# Generated by FakeRAM 2.0
VERSION 5.7 ;
BUSBITCHARS "[]" ;
PROPERTYDEFINITIONS
  MACRO width INTEGER ;
  MACRO depth INTEGER ;
  MACRO banks INTEGER ;
END PROPERTYDEFINITIONS
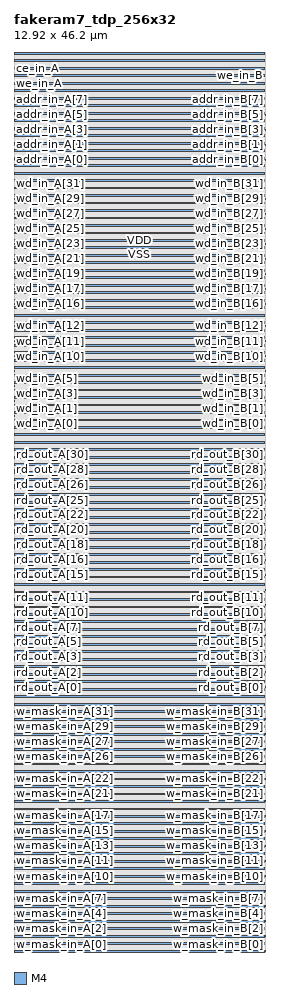
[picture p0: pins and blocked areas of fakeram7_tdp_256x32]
MACRO fakeram7_tdp_256x32
  PROPERTY width 32 ;
  PROPERTY depth 256 ;
  PROPERTY banks 2 ;
  FOREIGN fakeram7_tdp_256x32 0 0 ;
  SYMMETRY X Y ;
  SIZE 12.920 BY 46.200 ;
  CLASS BLOCK ;
  PIN w_mask_in_A[0]
    DIRECTION INPUT ;
    USE SIGNAL ;
    SHAPE ABUTMENT ;
    PORT
      LAYER M4 ;
      RECT 0.000 0.048 0.024 0.072 ;
    END
  END w_mask_in_A[0]
  PIN w_mask_in_B[0]
    DIRECTION INPUT ;
    USE SIGNAL ;
    SHAPE ABUTMENT ;
    PORT
      LAYER M4 ;
      RECT 12.896 0.048 12.920 0.072 ;
    END
  END w_mask_in_B[0]
  PIN w_mask_in_A[1]
    DIRECTION INPUT ;
    USE SIGNAL ;
    SHAPE ABUTMENT ;
    PORT
      LAYER M4 ;
      RECT 0.000 0.432 0.024 0.456 ;
    END
  END w_mask_in_A[1]
  PIN w_mask_in_B[1]
    DIRECTION INPUT ;
    USE SIGNAL ;
    SHAPE ABUTMENT ;
    PORT
      LAYER M4 ;
      RECT 12.896 0.432 12.920 0.456 ;
    END
  END w_mask_in_B[1]
  PIN w_mask_in_A[2]
    DIRECTION INPUT ;
    USE SIGNAL ;
    SHAPE ABUTMENT ;
    PORT
      LAYER M4 ;
      RECT 0.000 0.816 0.024 0.840 ;
    END
  END w_mask_in_A[2]
  PIN w_mask_in_B[2]
    DIRECTION INPUT ;
    USE SIGNAL ;
    SHAPE ABUTMENT ;
    PORT
      LAYER M4 ;
      RECT 12.896 0.816 12.920 0.840 ;
    END
  END w_mask_in_B[2]
  PIN w_mask_in_A[3]
    DIRECTION INPUT ;
    USE SIGNAL ;
    SHAPE ABUTMENT ;
    PORT
      LAYER M4 ;
      RECT 0.000 1.200 0.024 1.224 ;
    END
  END w_mask_in_A[3]
  PIN w_mask_in_B[3]
    DIRECTION INPUT ;
    USE SIGNAL ;
    SHAPE ABUTMENT ;
    PORT
      LAYER M4 ;
      RECT 12.896 1.200 12.920 1.224 ;
    END
  END w_mask_in_B[3]
  PIN w_mask_in_A[4]
    DIRECTION INPUT ;
    USE SIGNAL ;
    SHAPE ABUTMENT ;
    PORT
      LAYER M4 ;
      RECT 0.000 1.584 0.024 1.608 ;
    END
  END w_mask_in_A[4]
  PIN w_mask_in_B[4]
    DIRECTION INPUT ;
    USE SIGNAL ;
    SHAPE ABUTMENT ;
    PORT
      LAYER M4 ;
      RECT 12.896 1.584 12.920 1.608 ;
    END
  END w_mask_in_B[4]
  PIN w_mask_in_A[5]
    DIRECTION INPUT ;
    USE SIGNAL ;
    SHAPE ABUTMENT ;
    PORT
      LAYER M4 ;
      RECT 0.000 1.968 0.024 1.992 ;
    END
  END w_mask_in_A[5]
  PIN w_mask_in_B[5]
    DIRECTION INPUT ;
    USE SIGNAL ;
    SHAPE ABUTMENT ;
    PORT
      LAYER M4 ;
      RECT 12.896 1.968 12.920 1.992 ;
    END
  END w_mask_in_B[5]
  PIN w_mask_in_A[6]
    DIRECTION INPUT ;
    USE SIGNAL ;
    SHAPE ABUTMENT ;
    PORT
      LAYER M4 ;
      RECT 0.000 2.352 0.024 2.376 ;
    END
  END w_mask_in_A[6]
  PIN w_mask_in_B[6]
    DIRECTION INPUT ;
    USE SIGNAL ;
    SHAPE ABUTMENT ;
    PORT
      LAYER M4 ;
      RECT 12.896 2.352 12.920 2.376 ;
    END
  END w_mask_in_B[6]
  PIN w_mask_in_A[7]
    DIRECTION INPUT ;
    USE SIGNAL ;
    SHAPE ABUTMENT ;
    PORT
      LAYER M4 ;
      RECT 0.000 2.736 0.024 2.760 ;
    END
  END w_mask_in_A[7]
  PIN w_mask_in_B[7]
    DIRECTION INPUT ;
    USE SIGNAL ;
    SHAPE ABUTMENT ;
    PORT
      LAYER M4 ;
      RECT 12.896 2.736 12.920 2.760 ;
    END
  END w_mask_in_B[7]
  PIN w_mask_in_A[8]
    DIRECTION INPUT ;
    USE SIGNAL ;
    SHAPE ABUTMENT ;
    PORT
      LAYER M4 ;
      RECT 0.000 3.120 0.024 3.144 ;
    END
  END w_mask_in_A[8]
  PIN w_mask_in_B[8]
    DIRECTION INPUT ;
    USE SIGNAL ;
    SHAPE ABUTMENT ;
    PORT
      LAYER M4 ;
      RECT 12.896 3.120 12.920 3.144 ;
    END
  END w_mask_in_B[8]
  PIN w_mask_in_A[9]
    DIRECTION INPUT ;
    USE SIGNAL ;
    SHAPE ABUTMENT ;
    PORT
      LAYER M4 ;
      RECT 0.000 3.504 0.024 3.528 ;
    END
  END w_mask_in_A[9]
  PIN w_mask_in_B[9]
    DIRECTION INPUT ;
    USE SIGNAL ;
    SHAPE ABUTMENT ;
    PORT
      LAYER M4 ;
      RECT 12.896 3.504 12.920 3.528 ;
    END
  END w_mask_in_B[9]
  PIN w_mask_in_A[10]
    DIRECTION INPUT ;
    USE SIGNAL ;
    SHAPE ABUTMENT ;
    PORT
      LAYER M4 ;
      RECT 0.000 3.888 0.024 3.912 ;
    END
  END w_mask_in_A[10]
  PIN w_mask_in_B[10]
    DIRECTION INPUT ;
    USE SIGNAL ;
    SHAPE ABUTMENT ;
    PORT
      LAYER M4 ;
      RECT 12.896 3.888 12.920 3.912 ;
    END
  END w_mask_in_B[10]
  PIN w_mask_in_A[11]
    DIRECTION INPUT ;
    USE SIGNAL ;
    SHAPE ABUTMENT ;
    PORT
      LAYER M4 ;
      RECT 0.000 4.272 0.024 4.296 ;
    END
  END w_mask_in_A[11]
  PIN w_mask_in_B[11]
    DIRECTION INPUT ;
    USE SIGNAL ;
    SHAPE ABUTMENT ;
    PORT
      LAYER M4 ;
      RECT 12.896 4.272 12.920 4.296 ;
    END
  END w_mask_in_B[11]
  PIN w_mask_in_A[12]
    DIRECTION INPUT ;
    USE SIGNAL ;
    SHAPE ABUTMENT ;
    PORT
      LAYER M4 ;
      RECT 0.000 4.656 0.024 4.680 ;
    END
  END w_mask_in_A[12]
  PIN w_mask_in_B[12]
    DIRECTION INPUT ;
    USE SIGNAL ;
    SHAPE ABUTMENT ;
    PORT
      LAYER M4 ;
      RECT 12.896 4.656 12.920 4.680 ;
    END
  END w_mask_in_B[12]
  PIN w_mask_in_A[13]
    DIRECTION INPUT ;
    USE SIGNAL ;
    SHAPE ABUTMENT ;
    PORT
      LAYER M4 ;
      RECT 0.000 5.040 0.024 5.064 ;
    END
  END w_mask_in_A[13]
  PIN w_mask_in_B[13]
    DIRECTION INPUT ;
    USE SIGNAL ;
    SHAPE ABUTMENT ;
    PORT
      LAYER M4 ;
      RECT 12.896 5.040 12.920 5.064 ;
    END
  END w_mask_in_B[13]
  PIN w_mask_in_A[14]
    DIRECTION INPUT ;
    USE SIGNAL ;
    SHAPE ABUTMENT ;
    PORT
      LAYER M4 ;
      RECT 0.000 5.424 0.024 5.448 ;
    END
  END w_mask_in_A[14]
  PIN w_mask_in_B[14]
    DIRECTION INPUT ;
    USE SIGNAL ;
    SHAPE ABUTMENT ;
    PORT
      LAYER M4 ;
      RECT 12.896 5.424 12.920 5.448 ;
    END
  END w_mask_in_B[14]
  PIN w_mask_in_A[15]
    DIRECTION INPUT ;
    USE SIGNAL ;
    SHAPE ABUTMENT ;
    PORT
      LAYER M4 ;
      RECT 0.000 5.808 0.024 5.832 ;
    END
  END w_mask_in_A[15]
  PIN w_mask_in_B[15]
    DIRECTION INPUT ;
    USE SIGNAL ;
    SHAPE ABUTMENT ;
    PORT
      LAYER M4 ;
      RECT 12.896 5.808 12.920 5.832 ;
    END
  END w_mask_in_B[15]
  PIN w_mask_in_A[16]
    DIRECTION INPUT ;
    USE SIGNAL ;
    SHAPE ABUTMENT ;
    PORT
      LAYER M4 ;
      RECT 0.000 6.192 0.024 6.216 ;
    END
  END w_mask_in_A[16]
  PIN w_mask_in_B[16]
    DIRECTION INPUT ;
    USE SIGNAL ;
    SHAPE ABUTMENT ;
    PORT
      LAYER M4 ;
      RECT 12.896 6.192 12.920 6.216 ;
    END
  END w_mask_in_B[16]
  PIN w_mask_in_A[17]
    DIRECTION INPUT ;
    USE SIGNAL ;
    SHAPE ABUTMENT ;
    PORT
      LAYER M4 ;
      RECT 0.000 6.576 0.024 6.600 ;
    END
  END w_mask_in_A[17]
  PIN w_mask_in_B[17]
    DIRECTION INPUT ;
    USE SIGNAL ;
    SHAPE ABUTMENT ;
    PORT
      LAYER M4 ;
      RECT 12.896 6.576 12.920 6.600 ;
    END
  END w_mask_in_B[17]
  PIN w_mask_in_A[18]
    DIRECTION INPUT ;
    USE SIGNAL ;
    SHAPE ABUTMENT ;
    PORT
      LAYER M4 ;
      RECT 0.000 6.960 0.024 6.984 ;
    END
  END w_mask_in_A[18]
  PIN w_mask_in_B[18]
    DIRECTION INPUT ;
    USE SIGNAL ;
    SHAPE ABUTMENT ;
    PORT
      LAYER M4 ;
      RECT 12.896 6.960 12.920 6.984 ;
    END
  END w_mask_in_B[18]
  PIN w_mask_in_A[19]
    DIRECTION INPUT ;
    USE SIGNAL ;
    SHAPE ABUTMENT ;
    PORT
      LAYER M4 ;
      RECT 0.000 7.344 0.024 7.368 ;
    END
  END w_mask_in_A[19]
  PIN w_mask_in_B[19]
    DIRECTION INPUT ;
    USE SIGNAL ;
    SHAPE ABUTMENT ;
    PORT
      LAYER M4 ;
      RECT 12.896 7.344 12.920 7.368 ;
    END
  END w_mask_in_B[19]
  PIN w_mask_in_A[20]
    DIRECTION INPUT ;
    USE SIGNAL ;
    SHAPE ABUTMENT ;
    PORT
      LAYER M4 ;
      RECT 0.000 7.728 0.024 7.752 ;
    END
  END w_mask_in_A[20]
  PIN w_mask_in_B[20]
    DIRECTION INPUT ;
    USE SIGNAL ;
    SHAPE ABUTMENT ;
    PORT
      LAYER M4 ;
      RECT 12.896 7.728 12.920 7.752 ;
    END
  END w_mask_in_B[20]
  PIN w_mask_in_A[21]
    DIRECTION INPUT ;
    USE SIGNAL ;
    SHAPE ABUTMENT ;
    PORT
      LAYER M4 ;
      RECT 0.000 8.112 0.024 8.136 ;
    END
  END w_mask_in_A[21]
  PIN w_mask_in_B[21]
    DIRECTION INPUT ;
    USE SIGNAL ;
    SHAPE ABUTMENT ;
    PORT
      LAYER M4 ;
      RECT 12.896 8.112 12.920 8.136 ;
    END
  END w_mask_in_B[21]
  PIN w_mask_in_A[22]
    DIRECTION INPUT ;
    USE SIGNAL ;
    SHAPE ABUTMENT ;
    PORT
      LAYER M4 ;
      RECT 0.000 8.496 0.024 8.520 ;
    END
  END w_mask_in_A[22]
  PIN w_mask_in_B[22]
    DIRECTION INPUT ;
    USE SIGNAL ;
    SHAPE ABUTMENT ;
    PORT
      LAYER M4 ;
      RECT 12.896 8.496 12.920 8.520 ;
    END
  END w_mask_in_B[22]
  PIN w_mask_in_A[23]
    DIRECTION INPUT ;
    USE SIGNAL ;
    SHAPE ABUTMENT ;
    PORT
      LAYER M4 ;
      RECT 0.000 8.880 0.024 8.904 ;
    END
  END w_mask_in_A[23]
  PIN w_mask_in_B[23]
    DIRECTION INPUT ;
    USE SIGNAL ;
    SHAPE ABUTMENT ;
    PORT
      LAYER M4 ;
      RECT 12.896 8.880 12.920 8.904 ;
    END
  END w_mask_in_B[23]
  PIN w_mask_in_A[24]
    DIRECTION INPUT ;
    USE SIGNAL ;
    SHAPE ABUTMENT ;
    PORT
      LAYER M4 ;
      RECT 0.000 9.264 0.024 9.288 ;
    END
  END w_mask_in_A[24]
  PIN w_mask_in_B[24]
    DIRECTION INPUT ;
    USE SIGNAL ;
    SHAPE ABUTMENT ;
    PORT
      LAYER M4 ;
      RECT 12.896 9.264 12.920 9.288 ;
    END
  END w_mask_in_B[24]
  PIN w_mask_in_A[25]
    DIRECTION INPUT ;
    USE SIGNAL ;
    SHAPE ABUTMENT ;
    PORT
      LAYER M4 ;
      RECT 0.000 9.648 0.024 9.672 ;
    END
  END w_mask_in_A[25]
  PIN w_mask_in_B[25]
    DIRECTION INPUT ;
    USE SIGNAL ;
    SHAPE ABUTMENT ;
    PORT
      LAYER M4 ;
      RECT 12.896 9.648 12.920 9.672 ;
    END
  END w_mask_in_B[25]
  PIN w_mask_in_A[26]
    DIRECTION INPUT ;
    USE SIGNAL ;
    SHAPE ABUTMENT ;
    PORT
      LAYER M4 ;
      RECT 0.000 10.032 0.024 10.056 ;
    END
  END w_mask_in_A[26]
  PIN w_mask_in_B[26]
    DIRECTION INPUT ;
    USE SIGNAL ;
    SHAPE ABUTMENT ;
    PORT
      LAYER M4 ;
      RECT 12.896 10.032 12.920 10.056 ;
    END
  END w_mask_in_B[26]
  PIN w_mask_in_A[27]
    DIRECTION INPUT ;
    USE SIGNAL ;
    SHAPE ABUTMENT ;
    PORT
      LAYER M4 ;
      RECT 0.000 10.416 0.024 10.440 ;
    END
  END w_mask_in_A[27]
  PIN w_mask_in_B[27]
    DIRECTION INPUT ;
    USE SIGNAL ;
    SHAPE ABUTMENT ;
    PORT
      LAYER M4 ;
      RECT 12.896 10.416 12.920 10.440 ;
    END
  END w_mask_in_B[27]
  PIN w_mask_in_A[28]
    DIRECTION INPUT ;
    USE SIGNAL ;
    SHAPE ABUTMENT ;
    PORT
      LAYER M4 ;
      RECT 0.000 10.800 0.024 10.824 ;
    END
  END w_mask_in_A[28]
  PIN w_mask_in_B[28]
    DIRECTION INPUT ;
    USE SIGNAL ;
    SHAPE ABUTMENT ;
    PORT
      LAYER M4 ;
      RECT 12.896 10.800 12.920 10.824 ;
    END
  END w_mask_in_B[28]
  PIN w_mask_in_A[29]
    DIRECTION INPUT ;
    USE SIGNAL ;
    SHAPE ABUTMENT ;
    PORT
      LAYER M4 ;
      RECT 0.000 11.184 0.024 11.208 ;
    END
  END w_mask_in_A[29]
  PIN w_mask_in_B[29]
    DIRECTION INPUT ;
    USE SIGNAL ;
    SHAPE ABUTMENT ;
    PORT
      LAYER M4 ;
      RECT 12.896 11.184 12.920 11.208 ;
    END
  END w_mask_in_B[29]
  PIN w_mask_in_A[30]
    DIRECTION INPUT ;
    USE SIGNAL ;
    SHAPE ABUTMENT ;
    PORT
      LAYER M4 ;
      RECT 0.000 11.568 0.024 11.592 ;
    END
  END w_mask_in_A[30]
  PIN w_mask_in_B[30]
    DIRECTION INPUT ;
    USE SIGNAL ;
    SHAPE ABUTMENT ;
    PORT
      LAYER M4 ;
      RECT 12.896 11.568 12.920 11.592 ;
    END
  END w_mask_in_B[30]
  PIN w_mask_in_A[31]
    DIRECTION INPUT ;
    USE SIGNAL ;
    SHAPE ABUTMENT ;
    PORT
      LAYER M4 ;
      RECT 0.000 11.952 0.024 11.976 ;
    END
  END w_mask_in_A[31]
  PIN w_mask_in_B[31]
    DIRECTION INPUT ;
    USE SIGNAL ;
    SHAPE ABUTMENT ;
    PORT
      LAYER M4 ;
      RECT 12.896 11.952 12.920 11.976 ;
    END
  END w_mask_in_B[31]
  PIN rd_out_A[0]
    DIRECTION OUTPUT ;
    USE SIGNAL ;
    SHAPE ABUTMENT ;
    PORT
      LAYER M4 ;
      RECT 0.000 13.584 0.024 13.608 ;
    END
  END rd_out_A[0]
  PIN rd_out_B[0]
    DIRECTION OUTPUT ;
    USE SIGNAL ;
    SHAPE ABUTMENT ;
    PORT
      LAYER M4 ;
      RECT 12.896 13.584 12.920 13.608 ;
    END
  END rd_out_B[0]
  PIN rd_out_A[1]
    DIRECTION OUTPUT ;
    USE SIGNAL ;
    SHAPE ABUTMENT ;
    PORT
      LAYER M4 ;
      RECT 0.000 13.968 0.024 13.992 ;
    END
  END rd_out_A[1]
  PIN rd_out_B[1]
    DIRECTION OUTPUT ;
    USE SIGNAL ;
    SHAPE ABUTMENT ;
    PORT
      LAYER M4 ;
      RECT 12.896 13.968 12.920 13.992 ;
    END
  END rd_out_B[1]
  PIN rd_out_A[2]
    DIRECTION OUTPUT ;
    USE SIGNAL ;
    SHAPE ABUTMENT ;
    PORT
      LAYER M4 ;
      RECT 0.000 14.352 0.024 14.376 ;
    END
  END rd_out_A[2]
  PIN rd_out_B[2]
    DIRECTION OUTPUT ;
    USE SIGNAL ;
    SHAPE ABUTMENT ;
    PORT
      LAYER M4 ;
      RECT 12.896 14.352 12.920 14.376 ;
    END
  END rd_out_B[2]
  PIN rd_out_A[3]
    DIRECTION OUTPUT ;
    USE SIGNAL ;
    SHAPE ABUTMENT ;
    PORT
      LAYER M4 ;
      RECT 0.000 14.736 0.024 14.760 ;
    END
  END rd_out_A[3]
  PIN rd_out_B[3]
    DIRECTION OUTPUT ;
    USE SIGNAL ;
    SHAPE ABUTMENT ;
    PORT
      LAYER M4 ;
      RECT 12.896 14.736 12.920 14.760 ;
    END
  END rd_out_B[3]
  PIN rd_out_A[4]
    DIRECTION OUTPUT ;
    USE SIGNAL ;
    SHAPE ABUTMENT ;
    PORT
      LAYER M4 ;
      RECT 0.000 15.120 0.024 15.144 ;
    END
  END rd_out_A[4]
  PIN rd_out_B[4]
    DIRECTION OUTPUT ;
    USE SIGNAL ;
    SHAPE ABUTMENT ;
    PORT
      LAYER M4 ;
      RECT 12.896 15.120 12.920 15.144 ;
    END
  END rd_out_B[4]
  PIN rd_out_A[5]
    DIRECTION OUTPUT ;
    USE SIGNAL ;
    SHAPE ABUTMENT ;
    PORT
      LAYER M4 ;
      RECT 0.000 15.504 0.024 15.528 ;
    END
  END rd_out_A[5]
  PIN rd_out_B[5]
    DIRECTION OUTPUT ;
    USE SIGNAL ;
    SHAPE ABUTMENT ;
    PORT
      LAYER M4 ;
      RECT 12.896 15.504 12.920 15.528 ;
    END
  END rd_out_B[5]
  PIN rd_out_A[6]
    DIRECTION OUTPUT ;
    USE SIGNAL ;
    SHAPE ABUTMENT ;
    PORT
      LAYER M4 ;
      RECT 0.000 15.888 0.024 15.912 ;
    END
  END rd_out_A[6]
  PIN rd_out_B[6]
    DIRECTION OUTPUT ;
    USE SIGNAL ;
    SHAPE ABUTMENT ;
    PORT
      LAYER M4 ;
      RECT 12.896 15.888 12.920 15.912 ;
    END
  END rd_out_B[6]
  PIN rd_out_A[7]
    DIRECTION OUTPUT ;
    USE SIGNAL ;
    SHAPE ABUTMENT ;
    PORT
      LAYER M4 ;
      RECT 0.000 16.272 0.024 16.296 ;
    END
  END rd_out_A[7]
  PIN rd_out_B[7]
    DIRECTION OUTPUT ;
    USE SIGNAL ;
    SHAPE ABUTMENT ;
    PORT
      LAYER M4 ;
      RECT 12.896 16.272 12.920 16.296 ;
    END
  END rd_out_B[7]
  PIN rd_out_A[8]
    DIRECTION OUTPUT ;
    USE SIGNAL ;
    SHAPE ABUTMENT ;
    PORT
      LAYER M4 ;
      RECT 0.000 16.656 0.024 16.680 ;
    END
  END rd_out_A[8]
  PIN rd_out_B[8]
    DIRECTION OUTPUT ;
    USE SIGNAL ;
    SHAPE ABUTMENT ;
    PORT
      LAYER M4 ;
      RECT 12.896 16.656 12.920 16.680 ;
    END
  END rd_out_B[8]
  PIN rd_out_A[9]
    DIRECTION OUTPUT ;
    USE SIGNAL ;
    SHAPE ABUTMENT ;
    PORT
      LAYER M4 ;
      RECT 0.000 17.040 0.024 17.064 ;
    END
  END rd_out_A[9]
  PIN rd_out_B[9]
    DIRECTION OUTPUT ;
    USE SIGNAL ;
    SHAPE ABUTMENT ;
    PORT
      LAYER M4 ;
      RECT 12.896 17.040 12.920 17.064 ;
    END
  END rd_out_B[9]
  PIN rd_out_A[10]
    DIRECTION OUTPUT ;
    USE SIGNAL ;
    SHAPE ABUTMENT ;
    PORT
      LAYER M4 ;
      RECT 0.000 17.424 0.024 17.448 ;
    END
  END rd_out_A[10]
  PIN rd_out_B[10]
    DIRECTION OUTPUT ;
    USE SIGNAL ;
    SHAPE ABUTMENT ;
    PORT
      LAYER M4 ;
      RECT 12.896 17.424 12.920 17.448 ;
    END
  END rd_out_B[10]
  PIN rd_out_A[11]
    DIRECTION OUTPUT ;
    USE SIGNAL ;
    SHAPE ABUTMENT ;
    PORT
      LAYER M4 ;
      RECT 0.000 17.808 0.024 17.832 ;
    END
  END rd_out_A[11]
  PIN rd_out_B[11]
    DIRECTION OUTPUT ;
    USE SIGNAL ;
    SHAPE ABUTMENT ;
    PORT
      LAYER M4 ;
      RECT 12.896 17.808 12.920 17.832 ;
    END
  END rd_out_B[11]
  PIN rd_out_A[12]
    DIRECTION OUTPUT ;
    USE SIGNAL ;
    SHAPE ABUTMENT ;
    PORT
      LAYER M4 ;
      RECT 0.000 18.192 0.024 18.216 ;
    END
  END rd_out_A[12]
  PIN rd_out_B[12]
    DIRECTION OUTPUT ;
    USE SIGNAL ;
    SHAPE ABUTMENT ;
    PORT
      LAYER M4 ;
      RECT 12.896 18.192 12.920 18.216 ;
    END
  END rd_out_B[12]
  PIN rd_out_A[13]
    DIRECTION OUTPUT ;
    USE SIGNAL ;
    SHAPE ABUTMENT ;
    PORT
      LAYER M4 ;
      RECT 0.000 18.576 0.024 18.600 ;
    END
  END rd_out_A[13]
  PIN rd_out_B[13]
    DIRECTION OUTPUT ;
    USE SIGNAL ;
    SHAPE ABUTMENT ;
    PORT
      LAYER M4 ;
      RECT 12.896 18.576 12.920 18.600 ;
    END
  END rd_out_B[13]
  PIN rd_out_A[14]
    DIRECTION OUTPUT ;
    USE SIGNAL ;
    SHAPE ABUTMENT ;
    PORT
      LAYER M4 ;
      RECT 0.000 18.960 0.024 18.984 ;
    END
  END rd_out_A[14]
  PIN rd_out_B[14]
    DIRECTION OUTPUT ;
    USE SIGNAL ;
    SHAPE ABUTMENT ;
    PORT
      LAYER M4 ;
      RECT 12.896 18.960 12.920 18.984 ;
    END
  END rd_out_B[14]
  PIN rd_out_A[15]
    DIRECTION OUTPUT ;
    USE SIGNAL ;
    SHAPE ABUTMENT ;
    PORT
      LAYER M4 ;
      RECT 0.000 19.344 0.024 19.368 ;
    END
  END rd_out_A[15]
  PIN rd_out_B[15]
    DIRECTION OUTPUT ;
    USE SIGNAL ;
    SHAPE ABUTMENT ;
    PORT
      LAYER M4 ;
      RECT 12.896 19.344 12.920 19.368 ;
    END
  END rd_out_B[15]
  PIN rd_out_A[16]
    DIRECTION OUTPUT ;
    USE SIGNAL ;
    SHAPE ABUTMENT ;
    PORT
      LAYER M4 ;
      RECT 0.000 19.728 0.024 19.752 ;
    END
  END rd_out_A[16]
  PIN rd_out_B[16]
    DIRECTION OUTPUT ;
    USE SIGNAL ;
    SHAPE ABUTMENT ;
    PORT
      LAYER M4 ;
      RECT 12.896 19.728 12.920 19.752 ;
    END
  END rd_out_B[16]
  PIN rd_out_A[17]
    DIRECTION OUTPUT ;
    USE SIGNAL ;
    SHAPE ABUTMENT ;
    PORT
      LAYER M4 ;
      RECT 0.000 20.112 0.024 20.136 ;
    END
  END rd_out_A[17]
  PIN rd_out_B[17]
    DIRECTION OUTPUT ;
    USE SIGNAL ;
    SHAPE ABUTMENT ;
    PORT
      LAYER M4 ;
      RECT 12.896 20.112 12.920 20.136 ;
    END
  END rd_out_B[17]
  PIN rd_out_A[18]
    DIRECTION OUTPUT ;
    USE SIGNAL ;
    SHAPE ABUTMENT ;
    PORT
      LAYER M4 ;
      RECT 0.000 20.496 0.024 20.520 ;
    END
  END rd_out_A[18]
  PIN rd_out_B[18]
    DIRECTION OUTPUT ;
    USE SIGNAL ;
    SHAPE ABUTMENT ;
    PORT
      LAYER M4 ;
      RECT 12.896 20.496 12.920 20.520 ;
    END
  END rd_out_B[18]
  PIN rd_out_A[19]
    DIRECTION OUTPUT ;
    USE SIGNAL ;
    SHAPE ABUTMENT ;
    PORT
      LAYER M4 ;
      RECT 0.000 20.880 0.024 20.904 ;
    END
  END rd_out_A[19]
  PIN rd_out_B[19]
    DIRECTION OUTPUT ;
    USE SIGNAL ;
    SHAPE ABUTMENT ;
    PORT
      LAYER M4 ;
      RECT 12.896 20.880 12.920 20.904 ;
    END
  END rd_out_B[19]
  PIN rd_out_A[20]
    DIRECTION OUTPUT ;
    USE SIGNAL ;
    SHAPE ABUTMENT ;
    PORT
      LAYER M4 ;
      RECT 0.000 21.264 0.024 21.288 ;
    END
  END rd_out_A[20]
  PIN rd_out_B[20]
    DIRECTION OUTPUT ;
    USE SIGNAL ;
    SHAPE ABUTMENT ;
    PORT
      LAYER M4 ;
      RECT 12.896 21.264 12.920 21.288 ;
    END
  END rd_out_B[20]
  PIN rd_out_A[21]
    DIRECTION OUTPUT ;
    USE SIGNAL ;
    SHAPE ABUTMENT ;
    PORT
      LAYER M4 ;
      RECT 0.000 21.648 0.024 21.672 ;
    END
  END rd_out_A[21]
  PIN rd_out_B[21]
    DIRECTION OUTPUT ;
    USE SIGNAL ;
    SHAPE ABUTMENT ;
    PORT
      LAYER M4 ;
      RECT 12.896 21.648 12.920 21.672 ;
    END
  END rd_out_B[21]
  PIN rd_out_A[22]
    DIRECTION OUTPUT ;
    USE SIGNAL ;
    SHAPE ABUTMENT ;
    PORT
      LAYER M4 ;
      RECT 0.000 22.032 0.024 22.056 ;
    END
  END rd_out_A[22]
  PIN rd_out_B[22]
    DIRECTION OUTPUT ;
    USE SIGNAL ;
    SHAPE ABUTMENT ;
    PORT
      LAYER M4 ;
      RECT 12.896 22.032 12.920 22.056 ;
    END
  END rd_out_B[22]
  PIN rd_out_A[23]
    DIRECTION OUTPUT ;
    USE SIGNAL ;
    SHAPE ABUTMENT ;
    PORT
      LAYER M4 ;
      RECT 0.000 22.416 0.024 22.440 ;
    END
  END rd_out_A[23]
  PIN rd_out_B[23]
    DIRECTION OUTPUT ;
    USE SIGNAL ;
    SHAPE ABUTMENT ;
    PORT
      LAYER M4 ;
      RECT 12.896 22.416 12.920 22.440 ;
    END
  END rd_out_B[23]
  PIN rd_out_A[24]
    DIRECTION OUTPUT ;
    USE SIGNAL ;
    SHAPE ABUTMENT ;
    PORT
      LAYER M4 ;
      RECT 0.000 22.800 0.024 22.824 ;
    END
  END rd_out_A[24]
  PIN rd_out_B[24]
    DIRECTION OUTPUT ;
    USE SIGNAL ;
    SHAPE ABUTMENT ;
    PORT
      LAYER M4 ;
      RECT 12.896 22.800 12.920 22.824 ;
    END
  END rd_out_B[24]
  PIN rd_out_A[25]
    DIRECTION OUTPUT ;
    USE SIGNAL ;
    SHAPE ABUTMENT ;
    PORT
      LAYER M4 ;
      RECT 0.000 23.184 0.024 23.208 ;
    END
  END rd_out_A[25]
  PIN rd_out_B[25]
    DIRECTION OUTPUT ;
    USE SIGNAL ;
    SHAPE ABUTMENT ;
    PORT
      LAYER M4 ;
      RECT 12.896 23.184 12.920 23.208 ;
    END
  END rd_out_B[25]
  PIN rd_out_A[26]
    DIRECTION OUTPUT ;
    USE SIGNAL ;
    SHAPE ABUTMENT ;
    PORT
      LAYER M4 ;
      RECT 0.000 23.568 0.024 23.592 ;
    END
  END rd_out_A[26]
  PIN rd_out_B[26]
    DIRECTION OUTPUT ;
    USE SIGNAL ;
    SHAPE ABUTMENT ;
    PORT
      LAYER M4 ;
      RECT 12.896 23.568 12.920 23.592 ;
    END
  END rd_out_B[26]
  PIN rd_out_A[27]
    DIRECTION OUTPUT ;
    USE SIGNAL ;
    SHAPE ABUTMENT ;
    PORT
      LAYER M4 ;
      RECT 0.000 23.952 0.024 23.976 ;
    END
  END rd_out_A[27]
  PIN rd_out_B[27]
    DIRECTION OUTPUT ;
    USE SIGNAL ;
    SHAPE ABUTMENT ;
    PORT
      LAYER M4 ;
      RECT 12.896 23.952 12.920 23.976 ;
    END
  END rd_out_B[27]
  PIN rd_out_A[28]
    DIRECTION OUTPUT ;
    USE SIGNAL ;
    SHAPE ABUTMENT ;
    PORT
      LAYER M4 ;
      RECT 0.000 24.336 0.024 24.360 ;
    END
  END rd_out_A[28]
  PIN rd_out_B[28]
    DIRECTION OUTPUT ;
    USE SIGNAL ;
    SHAPE ABUTMENT ;
    PORT
      LAYER M4 ;
      RECT 12.896 24.336 12.920 24.360 ;
    END
  END rd_out_B[28]
  PIN rd_out_A[29]
    DIRECTION OUTPUT ;
    USE SIGNAL ;
    SHAPE ABUTMENT ;
    PORT
      LAYER M4 ;
      RECT 0.000 24.720 0.024 24.744 ;
    END
  END rd_out_A[29]
  PIN rd_out_B[29]
    DIRECTION OUTPUT ;
    USE SIGNAL ;
    SHAPE ABUTMENT ;
    PORT
      LAYER M4 ;
      RECT 12.896 24.720 12.920 24.744 ;
    END
  END rd_out_B[29]
  PIN rd_out_A[30]
    DIRECTION OUTPUT ;
    USE SIGNAL ;
    SHAPE ABUTMENT ;
    PORT
      LAYER M4 ;
      RECT 0.000 25.104 0.024 25.128 ;
    END
  END rd_out_A[30]
  PIN rd_out_B[30]
    DIRECTION OUTPUT ;
    USE SIGNAL ;
    SHAPE ABUTMENT ;
    PORT
      LAYER M4 ;
      RECT 12.896 25.104 12.920 25.128 ;
    END
  END rd_out_B[30]
  PIN rd_out_A[31]
    DIRECTION OUTPUT ;
    USE SIGNAL ;
    SHAPE ABUTMENT ;
    PORT
      LAYER M4 ;
      RECT 0.000 25.488 0.024 25.512 ;
    END
  END rd_out_A[31]
  PIN rd_out_B[31]
    DIRECTION OUTPUT ;
    USE SIGNAL ;
    SHAPE ABUTMENT ;
    PORT
      LAYER M4 ;
      RECT 12.896 25.488 12.920 25.512 ;
    END
  END rd_out_B[31]
  PIN wd_in_A[0]
    DIRECTION INPUT ;
    USE SIGNAL ;
    SHAPE ABUTMENT ;
    PORT
      LAYER M4 ;
      RECT 0.000 27.120 0.024 27.144 ;
    END
  END wd_in_A[0]
  PIN wd_in_B[0]
    DIRECTION INPUT ;
    USE SIGNAL ;
    SHAPE ABUTMENT ;
    PORT
      LAYER M4 ;
      RECT 12.896 27.120 12.920 27.144 ;
    END
  END wd_in_B[0]
  PIN wd_in_A[1]
    DIRECTION INPUT ;
    USE SIGNAL ;
    SHAPE ABUTMENT ;
    PORT
      LAYER M4 ;
      RECT 0.000 27.504 0.024 27.528 ;
    END
  END wd_in_A[1]
  PIN wd_in_B[1]
    DIRECTION INPUT ;
    USE SIGNAL ;
    SHAPE ABUTMENT ;
    PORT
      LAYER M4 ;
      RECT 12.896 27.504 12.920 27.528 ;
    END
  END wd_in_B[1]
  PIN wd_in_A[2]
    DIRECTION INPUT ;
    USE SIGNAL ;
    SHAPE ABUTMENT ;
    PORT
      LAYER M4 ;
      RECT 0.000 27.888 0.024 27.912 ;
    END
  END wd_in_A[2]
  PIN wd_in_B[2]
    DIRECTION INPUT ;
    USE SIGNAL ;
    SHAPE ABUTMENT ;
    PORT
      LAYER M4 ;
      RECT 12.896 27.888 12.920 27.912 ;
    END
  END wd_in_B[2]
  PIN wd_in_A[3]
    DIRECTION INPUT ;
    USE SIGNAL ;
    SHAPE ABUTMENT ;
    PORT
      LAYER M4 ;
      RECT 0.000 28.272 0.024 28.296 ;
    END
  END wd_in_A[3]
  PIN wd_in_B[3]
    DIRECTION INPUT ;
    USE SIGNAL ;
    SHAPE ABUTMENT ;
    PORT
      LAYER M4 ;
      RECT 12.896 28.272 12.920 28.296 ;
    END
  END wd_in_B[3]
  PIN wd_in_A[4]
    DIRECTION INPUT ;
    USE SIGNAL ;
    SHAPE ABUTMENT ;
    PORT
      LAYER M4 ;
      RECT 0.000 28.656 0.024 28.680 ;
    END
  END wd_in_A[4]
  PIN wd_in_B[4]
    DIRECTION INPUT ;
    USE SIGNAL ;
    SHAPE ABUTMENT ;
    PORT
      LAYER M4 ;
      RECT 12.896 28.656 12.920 28.680 ;
    END
  END wd_in_B[4]
  PIN wd_in_A[5]
    DIRECTION INPUT ;
    USE SIGNAL ;
    SHAPE ABUTMENT ;
    PORT
      LAYER M4 ;
      RECT 0.000 29.040 0.024 29.064 ;
    END
  END wd_in_A[5]
  PIN wd_in_B[5]
    DIRECTION INPUT ;
    USE SIGNAL ;
    SHAPE ABUTMENT ;
    PORT
      LAYER M4 ;
      RECT 12.896 29.040 12.920 29.064 ;
    END
  END wd_in_B[5]
  PIN wd_in_A[6]
    DIRECTION INPUT ;
    USE SIGNAL ;
    SHAPE ABUTMENT ;
    PORT
      LAYER M4 ;
      RECT 0.000 29.424 0.024 29.448 ;
    END
  END wd_in_A[6]
  PIN wd_in_B[6]
    DIRECTION INPUT ;
    USE SIGNAL ;
    SHAPE ABUTMENT ;
    PORT
      LAYER M4 ;
      RECT 12.896 29.424 12.920 29.448 ;
    END
  END wd_in_B[6]
  PIN wd_in_A[7]
    DIRECTION INPUT ;
    USE SIGNAL ;
    SHAPE ABUTMENT ;
    PORT
      LAYER M4 ;
      RECT 0.000 29.808 0.024 29.832 ;
    END
  END wd_in_A[7]
  PIN wd_in_B[7]
    DIRECTION INPUT ;
    USE SIGNAL ;
    SHAPE ABUTMENT ;
    PORT
      LAYER M4 ;
      RECT 12.896 29.808 12.920 29.832 ;
    END
  END wd_in_B[7]
  PIN wd_in_A[8]
    DIRECTION INPUT ;
    USE SIGNAL ;
    SHAPE ABUTMENT ;
    PORT
      LAYER M4 ;
      RECT 0.000 30.192 0.024 30.216 ;
    END
  END wd_in_A[8]
  PIN wd_in_B[8]
    DIRECTION INPUT ;
    USE SIGNAL ;
    SHAPE ABUTMENT ;
    PORT
      LAYER M4 ;
      RECT 12.896 30.192 12.920 30.216 ;
    END
  END wd_in_B[8]
  PIN wd_in_A[9]
    DIRECTION INPUT ;
    USE SIGNAL ;
    SHAPE ABUTMENT ;
    PORT
      LAYER M4 ;
      RECT 0.000 30.576 0.024 30.600 ;
    END
  END wd_in_A[9]
  PIN wd_in_B[9]
    DIRECTION INPUT ;
    USE SIGNAL ;
    SHAPE ABUTMENT ;
    PORT
      LAYER M4 ;
      RECT 12.896 30.576 12.920 30.600 ;
    END
  END wd_in_B[9]
  PIN wd_in_A[10]
    DIRECTION INPUT ;
    USE SIGNAL ;
    SHAPE ABUTMENT ;
    PORT
      LAYER M4 ;
      RECT 0.000 30.960 0.024 30.984 ;
    END
  END wd_in_A[10]
  PIN wd_in_B[10]
    DIRECTION INPUT ;
    USE SIGNAL ;
    SHAPE ABUTMENT ;
    PORT
      LAYER M4 ;
      RECT 12.896 30.960 12.920 30.984 ;
    END
  END wd_in_B[10]
  PIN wd_in_A[11]
    DIRECTION INPUT ;
    USE SIGNAL ;
    SHAPE ABUTMENT ;
    PORT
      LAYER M4 ;
      RECT 0.000 31.344 0.024 31.368 ;
    END
  END wd_in_A[11]
  PIN wd_in_B[11]
    DIRECTION INPUT ;
    USE SIGNAL ;
    SHAPE ABUTMENT ;
    PORT
      LAYER M4 ;
      RECT 12.896 31.344 12.920 31.368 ;
    END
  END wd_in_B[11]
  PIN wd_in_A[12]
    DIRECTION INPUT ;
    USE SIGNAL ;
    SHAPE ABUTMENT ;
    PORT
      LAYER M4 ;
      RECT 0.000 31.728 0.024 31.752 ;
    END
  END wd_in_A[12]
  PIN wd_in_B[12]
    DIRECTION INPUT ;
    USE SIGNAL ;
    SHAPE ABUTMENT ;
    PORT
      LAYER M4 ;
      RECT 12.896 31.728 12.920 31.752 ;
    END
  END wd_in_B[12]
  PIN wd_in_A[13]
    DIRECTION INPUT ;
    USE SIGNAL ;
    SHAPE ABUTMENT ;
    PORT
      LAYER M4 ;
      RECT 0.000 32.112 0.024 32.136 ;
    END
  END wd_in_A[13]
  PIN wd_in_B[13]
    DIRECTION INPUT ;
    USE SIGNAL ;
    SHAPE ABUTMENT ;
    PORT
      LAYER M4 ;
      RECT 12.896 32.112 12.920 32.136 ;
    END
  END wd_in_B[13]
  PIN wd_in_A[14]
    DIRECTION INPUT ;
    USE SIGNAL ;
    SHAPE ABUTMENT ;
    PORT
      LAYER M4 ;
      RECT 0.000 32.496 0.024 32.520 ;
    END
  END wd_in_A[14]
  PIN wd_in_B[14]
    DIRECTION INPUT ;
    USE SIGNAL ;
    SHAPE ABUTMENT ;
    PORT
      LAYER M4 ;
      RECT 12.896 32.496 12.920 32.520 ;
    END
  END wd_in_B[14]
  PIN wd_in_A[15]
    DIRECTION INPUT ;
    USE SIGNAL ;
    SHAPE ABUTMENT ;
    PORT
      LAYER M4 ;
      RECT 0.000 32.880 0.024 32.904 ;
    END
  END wd_in_A[15]
  PIN wd_in_B[15]
    DIRECTION INPUT ;
    USE SIGNAL ;
    SHAPE ABUTMENT ;
    PORT
      LAYER M4 ;
      RECT 12.896 32.880 12.920 32.904 ;
    END
  END wd_in_B[15]
  PIN wd_in_A[16]
    DIRECTION INPUT ;
    USE SIGNAL ;
    SHAPE ABUTMENT ;
    PORT
      LAYER M4 ;
      RECT 0.000 33.264 0.024 33.288 ;
    END
  END wd_in_A[16]
  PIN wd_in_B[16]
    DIRECTION INPUT ;
    USE SIGNAL ;
    SHAPE ABUTMENT ;
    PORT
      LAYER M4 ;
      RECT 12.896 33.264 12.920 33.288 ;
    END
  END wd_in_B[16]
  PIN wd_in_A[17]
    DIRECTION INPUT ;
    USE SIGNAL ;
    SHAPE ABUTMENT ;
    PORT
      LAYER M4 ;
      RECT 0.000 33.648 0.024 33.672 ;
    END
  END wd_in_A[17]
  PIN wd_in_B[17]
    DIRECTION INPUT ;
    USE SIGNAL ;
    SHAPE ABUTMENT ;
    PORT
      LAYER M4 ;
      RECT 12.896 33.648 12.920 33.672 ;
    END
  END wd_in_B[17]
  PIN wd_in_A[18]
    DIRECTION INPUT ;
    USE SIGNAL ;
    SHAPE ABUTMENT ;
    PORT
      LAYER M4 ;
      RECT 0.000 34.032 0.024 34.056 ;
    END
  END wd_in_A[18]
  PIN wd_in_B[18]
    DIRECTION INPUT ;
    USE SIGNAL ;
    SHAPE ABUTMENT ;
    PORT
      LAYER M4 ;
      RECT 12.896 34.032 12.920 34.056 ;
    END
  END wd_in_B[18]
  PIN wd_in_A[19]
    DIRECTION INPUT ;
    USE SIGNAL ;
    SHAPE ABUTMENT ;
    PORT
      LAYER M4 ;
      RECT 0.000 34.416 0.024 34.440 ;
    END
  END wd_in_A[19]
  PIN wd_in_B[19]
    DIRECTION INPUT ;
    USE SIGNAL ;
    SHAPE ABUTMENT ;
    PORT
      LAYER M4 ;
      RECT 12.896 34.416 12.920 34.440 ;
    END
  END wd_in_B[19]
  PIN wd_in_A[20]
    DIRECTION INPUT ;
    USE SIGNAL ;
    SHAPE ABUTMENT ;
    PORT
      LAYER M4 ;
      RECT 0.000 34.800 0.024 34.824 ;
    END
  END wd_in_A[20]
  PIN wd_in_B[20]
    DIRECTION INPUT ;
    USE SIGNAL ;
    SHAPE ABUTMENT ;
    PORT
      LAYER M4 ;
      RECT 12.896 34.800 12.920 34.824 ;
    END
  END wd_in_B[20]
  PIN wd_in_A[21]
    DIRECTION INPUT ;
    USE SIGNAL ;
    SHAPE ABUTMENT ;
    PORT
      LAYER M4 ;
      RECT 0.000 35.184 0.024 35.208 ;
    END
  END wd_in_A[21]
  PIN wd_in_B[21]
    DIRECTION INPUT ;
    USE SIGNAL ;
    SHAPE ABUTMENT ;
    PORT
      LAYER M4 ;
      RECT 12.896 35.184 12.920 35.208 ;
    END
  END wd_in_B[21]
  PIN wd_in_A[22]
    DIRECTION INPUT ;
    USE SIGNAL ;
    SHAPE ABUTMENT ;
    PORT
      LAYER M4 ;
      RECT 0.000 35.568 0.024 35.592 ;
    END
  END wd_in_A[22]
  PIN wd_in_B[22]
    DIRECTION INPUT ;
    USE SIGNAL ;
    SHAPE ABUTMENT ;
    PORT
      LAYER M4 ;
      RECT 12.896 35.568 12.920 35.592 ;
    END
  END wd_in_B[22]
  PIN wd_in_A[23]
    DIRECTION INPUT ;
    USE SIGNAL ;
    SHAPE ABUTMENT ;
    PORT
      LAYER M4 ;
      RECT 0.000 35.952 0.024 35.976 ;
    END
  END wd_in_A[23]
  PIN wd_in_B[23]
    DIRECTION INPUT ;
    USE SIGNAL ;
    SHAPE ABUTMENT ;
    PORT
      LAYER M4 ;
      RECT 12.896 35.952 12.920 35.976 ;
    END
  END wd_in_B[23]
  PIN wd_in_A[24]
    DIRECTION INPUT ;
    USE SIGNAL ;
    SHAPE ABUTMENT ;
    PORT
      LAYER M4 ;
      RECT 0.000 36.336 0.024 36.360 ;
    END
  END wd_in_A[24]
  PIN wd_in_B[24]
    DIRECTION INPUT ;
    USE SIGNAL ;
    SHAPE ABUTMENT ;
    PORT
      LAYER M4 ;
      RECT 12.896 36.336 12.920 36.360 ;
    END
  END wd_in_B[24]
  PIN wd_in_A[25]
    DIRECTION INPUT ;
    USE SIGNAL ;
    SHAPE ABUTMENT ;
    PORT
      LAYER M4 ;
      RECT 0.000 36.720 0.024 36.744 ;
    END
  END wd_in_A[25]
  PIN wd_in_B[25]
    DIRECTION INPUT ;
    USE SIGNAL ;
    SHAPE ABUTMENT ;
    PORT
      LAYER M4 ;
      RECT 12.896 36.720 12.920 36.744 ;
    END
  END wd_in_B[25]
  PIN wd_in_A[26]
    DIRECTION INPUT ;
    USE SIGNAL ;
    SHAPE ABUTMENT ;
    PORT
      LAYER M4 ;
      RECT 0.000 37.104 0.024 37.128 ;
    END
  END wd_in_A[26]
  PIN wd_in_B[26]
    DIRECTION INPUT ;
    USE SIGNAL ;
    SHAPE ABUTMENT ;
    PORT
      LAYER M4 ;
      RECT 12.896 37.104 12.920 37.128 ;
    END
  END wd_in_B[26]
  PIN wd_in_A[27]
    DIRECTION INPUT ;
    USE SIGNAL ;
    SHAPE ABUTMENT ;
    PORT
      LAYER M4 ;
      RECT 0.000 37.488 0.024 37.512 ;
    END
  END wd_in_A[27]
  PIN wd_in_B[27]
    DIRECTION INPUT ;
    USE SIGNAL ;
    SHAPE ABUTMENT ;
    PORT
      LAYER M4 ;
      RECT 12.896 37.488 12.920 37.512 ;
    END
  END wd_in_B[27]
  PIN wd_in_A[28]
    DIRECTION INPUT ;
    USE SIGNAL ;
    SHAPE ABUTMENT ;
    PORT
      LAYER M4 ;
      RECT 0.000 37.872 0.024 37.896 ;
    END
  END wd_in_A[28]
  PIN wd_in_B[28]
    DIRECTION INPUT ;
    USE SIGNAL ;
    SHAPE ABUTMENT ;
    PORT
      LAYER M4 ;
      RECT 12.896 37.872 12.920 37.896 ;
    END
  END wd_in_B[28]
  PIN wd_in_A[29]
    DIRECTION INPUT ;
    USE SIGNAL ;
    SHAPE ABUTMENT ;
    PORT
      LAYER M4 ;
      RECT 0.000 38.256 0.024 38.280 ;
    END
  END wd_in_A[29]
  PIN wd_in_B[29]
    DIRECTION INPUT ;
    USE SIGNAL ;
    SHAPE ABUTMENT ;
    PORT
      LAYER M4 ;
      RECT 12.896 38.256 12.920 38.280 ;
    END
  END wd_in_B[29]
  PIN wd_in_A[30]
    DIRECTION INPUT ;
    USE SIGNAL ;
    SHAPE ABUTMENT ;
    PORT
      LAYER M4 ;
      RECT 0.000 38.640 0.024 38.664 ;
    END
  END wd_in_A[30]
  PIN wd_in_B[30]
    DIRECTION INPUT ;
    USE SIGNAL ;
    SHAPE ABUTMENT ;
    PORT
      LAYER M4 ;
      RECT 12.896 38.640 12.920 38.664 ;
    END
  END wd_in_B[30]
  PIN wd_in_A[31]
    DIRECTION INPUT ;
    USE SIGNAL ;
    SHAPE ABUTMENT ;
    PORT
      LAYER M4 ;
      RECT 0.000 39.024 0.024 39.048 ;
    END
  END wd_in_A[31]
  PIN wd_in_B[31]
    DIRECTION INPUT ;
    USE SIGNAL ;
    SHAPE ABUTMENT ;
    PORT
      LAYER M4 ;
      RECT 12.896 39.024 12.920 39.048 ;
    END
  END wd_in_B[31]
  PIN addr_in_A[0]
    DIRECTION INPUT ;
    USE SIGNAL ;
    SHAPE ABUTMENT ;
    PORT
      LAYER M4 ;
      RECT 0.000 40.656 0.024 40.680 ;
    END
  END addr_in_A[0]
  PIN addr_in_B[0]
    DIRECTION INPUT ;
    USE SIGNAL ;
    SHAPE ABUTMENT ;
    PORT
      LAYER M4 ;
      RECT 12.896 40.656 12.920 40.680 ;
    END
  END addr_in_B[0]
  PIN addr_in_A[1]
    DIRECTION INPUT ;
    USE SIGNAL ;
    SHAPE ABUTMENT ;
    PORT
      LAYER M4 ;
      RECT 0.000 41.040 0.024 41.064 ;
    END
  END addr_in_A[1]
  PIN addr_in_B[1]
    DIRECTION INPUT ;
    USE SIGNAL ;
    SHAPE ABUTMENT ;
    PORT
      LAYER M4 ;
      RECT 12.896 41.040 12.920 41.064 ;
    END
  END addr_in_B[1]
  PIN addr_in_A[2]
    DIRECTION INPUT ;
    USE SIGNAL ;
    SHAPE ABUTMENT ;
    PORT
      LAYER M4 ;
      RECT 0.000 41.424 0.024 41.448 ;
    END
  END addr_in_A[2]
  PIN addr_in_B[2]
    DIRECTION INPUT ;
    USE SIGNAL ;
    SHAPE ABUTMENT ;
    PORT
      LAYER M4 ;
      RECT 12.896 41.424 12.920 41.448 ;
    END
  END addr_in_B[2]
  PIN addr_in_A[3]
    DIRECTION INPUT ;
    USE SIGNAL ;
    SHAPE ABUTMENT ;
    PORT
      LAYER M4 ;
      RECT 0.000 41.808 0.024 41.832 ;
    END
  END addr_in_A[3]
  PIN addr_in_B[3]
    DIRECTION INPUT ;
    USE SIGNAL ;
    SHAPE ABUTMENT ;
    PORT
      LAYER M4 ;
      RECT 12.896 41.808 12.920 41.832 ;
    END
  END addr_in_B[3]
  PIN addr_in_A[4]
    DIRECTION INPUT ;
    USE SIGNAL ;
    SHAPE ABUTMENT ;
    PORT
      LAYER M4 ;
      RECT 0.000 42.192 0.024 42.216 ;
    END
  END addr_in_A[4]
  PIN addr_in_B[4]
    DIRECTION INPUT ;
    USE SIGNAL ;
    SHAPE ABUTMENT ;
    PORT
      LAYER M4 ;
      RECT 12.896 42.192 12.920 42.216 ;
    END
  END addr_in_B[4]
  PIN addr_in_A[5]
    DIRECTION INPUT ;
    USE SIGNAL ;
    SHAPE ABUTMENT ;
    PORT
      LAYER M4 ;
      RECT 0.000 42.576 0.024 42.600 ;
    END
  END addr_in_A[5]
  PIN addr_in_B[5]
    DIRECTION INPUT ;
    USE SIGNAL ;
    SHAPE ABUTMENT ;
    PORT
      LAYER M4 ;
      RECT 12.896 42.576 12.920 42.600 ;
    END
  END addr_in_B[5]
  PIN addr_in_A[6]
    DIRECTION INPUT ;
    USE SIGNAL ;
    SHAPE ABUTMENT ;
    PORT
      LAYER M4 ;
      RECT 0.000 42.960 0.024 42.984 ;
    END
  END addr_in_A[6]
  PIN addr_in_B[6]
    DIRECTION INPUT ;
    USE SIGNAL ;
    SHAPE ABUTMENT ;
    PORT
      LAYER M4 ;
      RECT 12.896 42.960 12.920 42.984 ;
    END
  END addr_in_B[6]
  PIN addr_in_A[7]
    DIRECTION INPUT ;
    USE SIGNAL ;
    SHAPE ABUTMENT ;
    PORT
      LAYER M4 ;
      RECT 0.000 43.344 0.024 43.368 ;
    END
  END addr_in_A[7]
  PIN addr_in_B[7]
    DIRECTION INPUT ;
    USE SIGNAL ;
    SHAPE ABUTMENT ;
    PORT
      LAYER M4 ;
      RECT 12.896 43.344 12.920 43.368 ;
    END
  END addr_in_B[7]
  PIN we_in_A
    DIRECTION INPUT ;
    USE SIGNAL ;
    SHAPE ABUTMENT ;
    PORT
      LAYER M4 ;
      RECT 0.000 44.976 0.024 45.000 ;
    END
  END we_in_A
  PIN we_in_B
    DIRECTION INPUT ;
    USE SIGNAL ;
    SHAPE ABUTMENT ;
    PORT
      LAYER M4 ;
      RECT 12.896 44.976 12.920 45.000 ;
    END
  END we_in_B
  PIN ce_in_A
    DIRECTION INPUT ;
    USE SIGNAL ;
    SHAPE ABUTMENT ;
    PORT
      LAYER M4 ;
      RECT 0.000 45.360 0.024 45.384 ;
    END
  END ce_in_A
  PIN clk_A
    DIRECTION INPUT ;
    USE SIGNAL ;
    SHAPE ABUTMENT ;
    PORT
      LAYER M4 ;
      RECT 0.000 45.744 0.024 45.768 ;
    END
  END clk_A
  PIN ce_in_B
    DIRECTION INPUT ;
    USE SIGNAL ;
    SHAPE ABUTMENT ;
    PORT
      LAYER M4 ;
      RECT 0.000 46.128 0.024 46.152 ;
    END
  END ce_in_B
  PIN clk_B
    DIRECTION INPUT ;
    USE SIGNAL ;
    SHAPE ABUTMENT ;
    PORT
      LAYER M4 ;
      RECT 0.000 46.512 0.024 46.536 ;
    END
  END clk_B
  PIN VSS
    DIRECTION INOUT ;
    USE GROUND ;
    PORT
      LAYER M4 ;
      RECT 0.048 0.000 12.872 0.096 ;
      RECT 0.048 0.768 12.872 0.864 ;
      RECT 0.048 1.536 12.872 1.632 ;
      RECT 0.048 2.304 12.872 2.400 ;
      RECT 0.048 3.072 12.872 3.168 ;
      RECT 0.048 3.840 12.872 3.936 ;
      RECT 0.048 4.608 12.872 4.704 ;
      RECT 0.048 5.376 12.872 5.472 ;
      RECT 0.048 6.144 12.872 6.240 ;
      RECT 0.048 6.912 12.872 7.008 ;
      RECT 0.048 7.680 12.872 7.776 ;
      RECT 0.048 8.448 12.872 8.544 ;
      RECT 0.048 9.216 12.872 9.312 ;
      RECT 0.048 9.984 12.872 10.080 ;
      RECT 0.048 10.752 12.872 10.848 ;
      RECT 0.048 11.520 12.872 11.616 ;
      RECT 0.048 12.288 12.872 12.384 ;
      RECT 0.048 13.056 12.872 13.152 ;
      RECT 0.048 13.824 12.872 13.920 ;
      RECT 0.048 14.592 12.872 14.688 ;
      RECT 0.048 15.360 12.872 15.456 ;
      RECT 0.048 16.128 12.872 16.224 ;
      RECT 0.048 16.896 12.872 16.992 ;
      RECT 0.048 17.664 12.872 17.760 ;
      RECT 0.048 18.432 12.872 18.528 ;
      RECT 0.048 19.200 12.872 19.296 ;
      RECT 0.048 19.968 12.872 20.064 ;
      RECT 0.048 20.736 12.872 20.832 ;
      RECT 0.048 21.504 12.872 21.600 ;
      RECT 0.048 22.272 12.872 22.368 ;
      RECT 0.048 23.040 12.872 23.136 ;
      RECT 0.048 23.808 12.872 23.904 ;
      RECT 0.048 24.576 12.872 24.672 ;
      RECT 0.048 25.344 12.872 25.440 ;
      RECT 0.048 26.112 12.872 26.208 ;
      RECT 0.048 26.880 12.872 26.976 ;
      RECT 0.048 27.648 12.872 27.744 ;
      RECT 0.048 28.416 12.872 28.512 ;
      RECT 0.048 29.184 12.872 29.280 ;
      RECT 0.048 29.952 12.872 30.048 ;
      RECT 0.048 30.720 12.872 30.816 ;
      RECT 0.048 31.488 12.872 31.584 ;
      RECT 0.048 32.256 12.872 32.352 ;
      RECT 0.048 33.024 12.872 33.120 ;
      RECT 0.048 33.792 12.872 33.888 ;
      RECT 0.048 34.560 12.872 34.656 ;
      RECT 0.048 35.328 12.872 35.424 ;
      RECT 0.048 36.096 12.872 36.192 ;
      RECT 0.048 36.864 12.872 36.960 ;
      RECT 0.048 37.632 12.872 37.728 ;
      RECT 0.048 38.400 12.872 38.496 ;
      RECT 0.048 39.168 12.872 39.264 ;
      RECT 0.048 39.936 12.872 40.032 ;
      RECT 0.048 40.704 12.872 40.800 ;
      RECT 0.048 41.472 12.872 41.568 ;
      RECT 0.048 42.240 12.872 42.336 ;
      RECT 0.048 43.008 12.872 43.104 ;
      RECT 0.048 43.776 12.872 43.872 ;
      RECT 0.048 44.544 12.872 44.640 ;
      RECT 0.048 45.312 12.872 45.408 ;
      RECT 0.048 46.080 12.872 46.176 ;
    END
  END VSS
  PIN VDD
    DIRECTION INOUT ;
    USE POWER ;
    PORT
      LAYER M4 ;
      RECT 0.048 0.384 12.872 0.480 ;
      RECT 0.048 1.152 12.872 1.248 ;
      RECT 0.048 1.920 12.872 2.016 ;
      RECT 0.048 2.688 12.872 2.784 ;
      RECT 0.048 3.456 12.872 3.552 ;
      RECT 0.048 4.224 12.872 4.320 ;
      RECT 0.048 4.992 12.872 5.088 ;
      RECT 0.048 5.760 12.872 5.856 ;
      RECT 0.048 6.528 12.872 6.624 ;
      RECT 0.048 7.296 12.872 7.392 ;
      RECT 0.048 8.064 12.872 8.160 ;
      RECT 0.048 8.832 12.872 8.928 ;
      RECT 0.048 9.600 12.872 9.696 ;
      RECT 0.048 10.368 12.872 10.464 ;
      RECT 0.048 11.136 12.872 11.232 ;
      RECT 0.048 11.904 12.872 12.000 ;
      RECT 0.048 12.672 12.872 12.768 ;
      RECT 0.048 13.440 12.872 13.536 ;
      RECT 0.048 14.208 12.872 14.304 ;
      RECT 0.048 14.976 12.872 15.072 ;
      RECT 0.048 15.744 12.872 15.840 ;
      RECT 0.048 16.512 12.872 16.608 ;
      RECT 0.048 17.280 12.872 17.376 ;
      RECT 0.048 18.048 12.872 18.144 ;
      RECT 0.048 18.816 12.872 18.912 ;
      RECT 0.048 19.584 12.872 19.680 ;
      RECT 0.048 20.352 12.872 20.448 ;
      RECT 0.048 21.120 12.872 21.216 ;
      RECT 0.048 21.888 12.872 21.984 ;
      RECT 0.048 22.656 12.872 22.752 ;
      RECT 0.048 23.424 12.872 23.520 ;
      RECT 0.048 24.192 12.872 24.288 ;
      RECT 0.048 24.960 12.872 25.056 ;
      RECT 0.048 25.728 12.872 25.824 ;
      RECT 0.048 26.496 12.872 26.592 ;
      RECT 0.048 27.264 12.872 27.360 ;
      RECT 0.048 28.032 12.872 28.128 ;
      RECT 0.048 28.800 12.872 28.896 ;
      RECT 0.048 29.568 12.872 29.664 ;
      RECT 0.048 30.336 12.872 30.432 ;
      RECT 0.048 31.104 12.872 31.200 ;
      RECT 0.048 31.872 12.872 31.968 ;
      RECT 0.048 32.640 12.872 32.736 ;
      RECT 0.048 33.408 12.872 33.504 ;
      RECT 0.048 34.176 12.872 34.272 ;
      RECT 0.048 34.944 12.872 35.040 ;
      RECT 0.048 35.712 12.872 35.808 ;
      RECT 0.048 36.480 12.872 36.576 ;
      RECT 0.048 37.248 12.872 37.344 ;
      RECT 0.048 38.016 12.872 38.112 ;
      RECT 0.048 38.784 12.872 38.880 ;
      RECT 0.048 39.552 12.872 39.648 ;
      RECT 0.048 40.320 12.872 40.416 ;
      RECT 0.048 41.088 12.872 41.184 ;
      RECT 0.048 41.856 12.872 41.952 ;
      RECT 0.048 42.624 12.872 42.720 ;
      RECT 0.048 43.392 12.872 43.488 ;
      RECT 0.048 44.160 12.872 44.256 ;
      RECT 0.048 44.928 12.872 45.024 ;
      RECT 0.048 45.696 12.872 45.792 ;
    END
  END VDD
  OBS
    LAYER M1 ;
    RECT 0 0 12.920 46.200 ;
    LAYER M2 ;
    RECT 0 0 12.920 46.200 ;
    LAYER M3 ;
    RECT 0 0 12.920 46.200 ;
    LAYER M4 ;
    RECT 0 0 12.920 46.200 ;
  END
END fakeram7_tdp_256x32

END LIBRARY
